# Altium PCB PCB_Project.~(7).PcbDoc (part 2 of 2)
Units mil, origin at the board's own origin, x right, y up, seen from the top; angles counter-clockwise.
Board outline 8500 x 3000 mil, 2 copper layers (Top Layer, Bottom Layer), stack 62 mil thick; 104 components, 48 nets, 317 pads, 0 vias.
Unrouted connection lines stored in the file: 193.

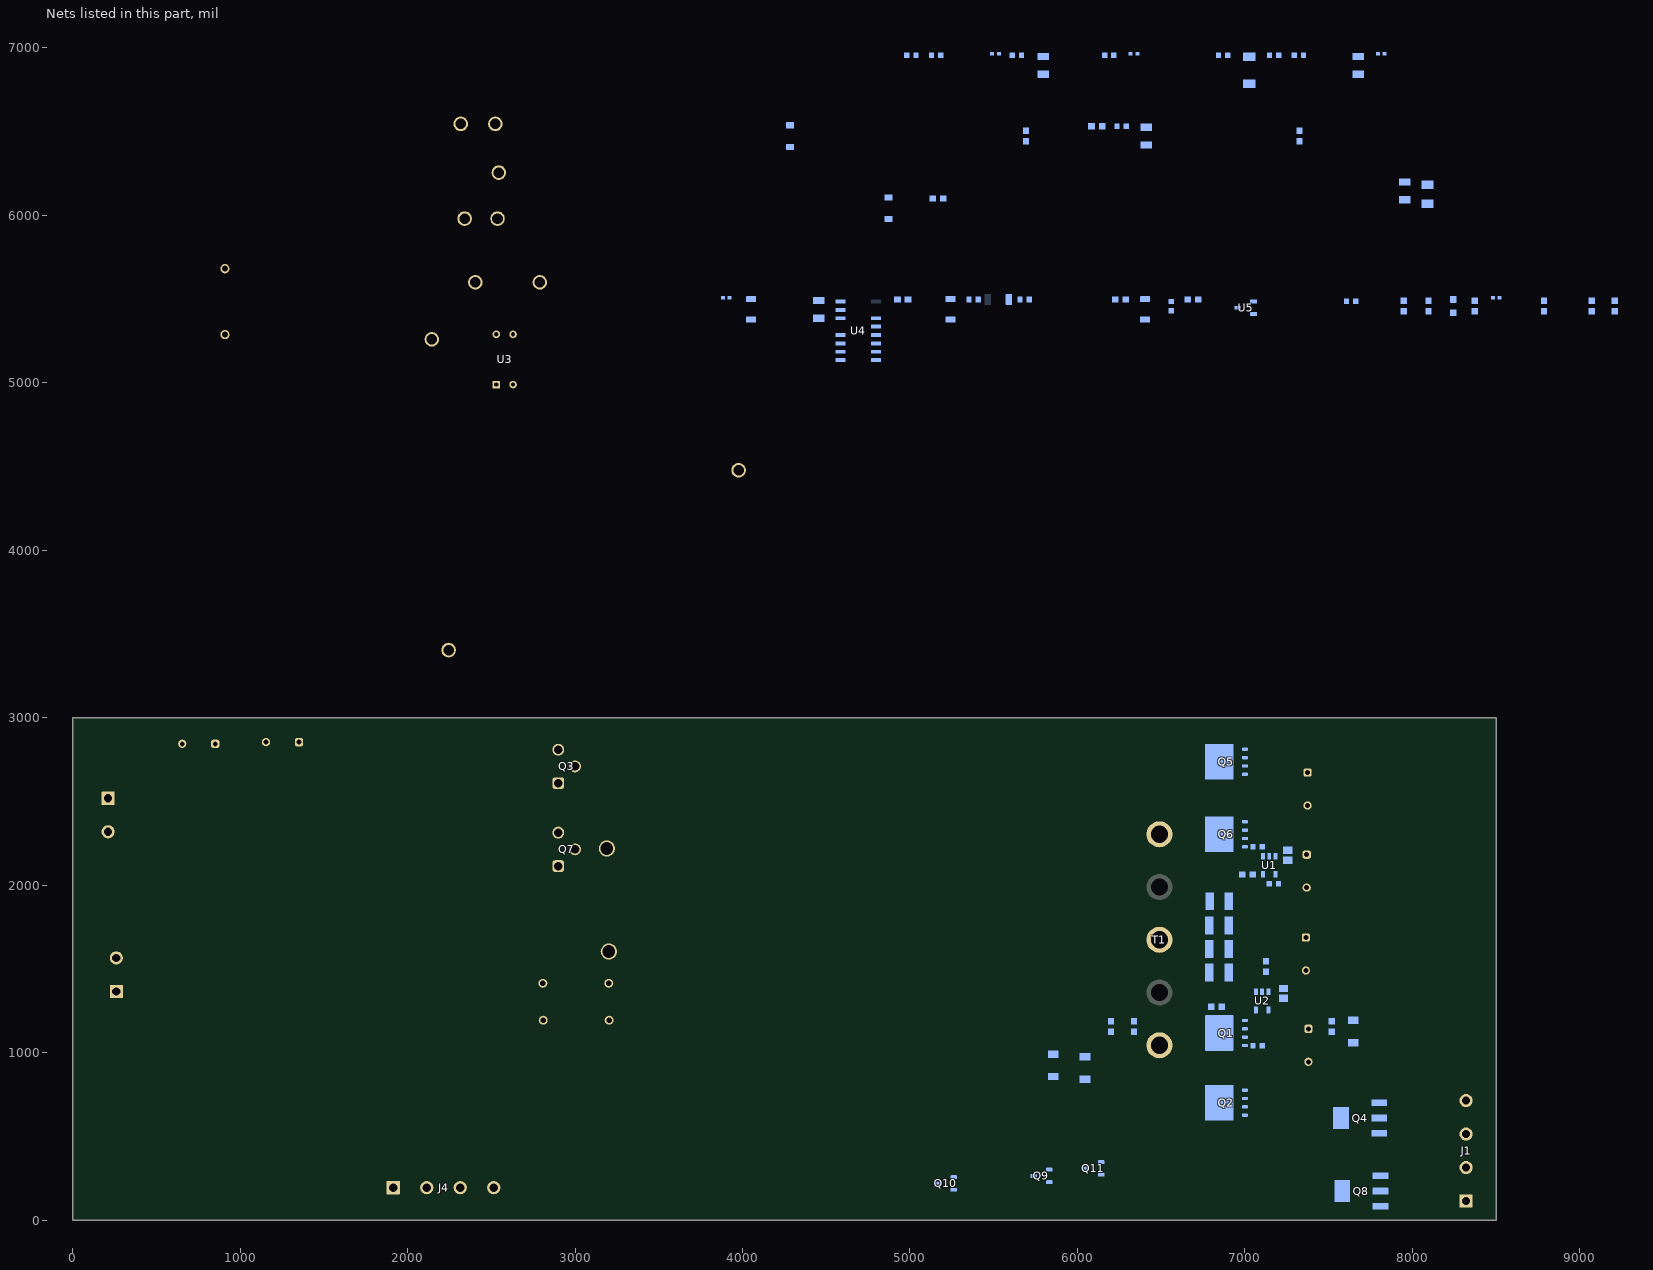
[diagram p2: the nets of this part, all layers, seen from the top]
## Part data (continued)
C15: library part CMP-0009595-2, "CAP, CERM, 1000 pF,  V, +/- 20%, E, D7xT6mm", Cap_Case=7x6x11mm, Manufacturer=TDK, Supplier Part Number 1=445-174535-ND, TempCo=E, Tolerance_%=20%, Value1=Unknown, Value2=V, ValueDisplayed=1000pF
C16: library part CMP-0008462-2, "CAP, CERM, 100 pF, 100 V, +/- 5%, C0G/NP0, 1206", Cap_Case=1206, Manufacturer=AVX, Supplier Part Number 1=478-1444-1-ND, TempCo=C0G/NP0, Tolerance_%=5%, Value1="0.701 ohm", Value2=100V, ValueDisplayed=100pF
C17 C21: library part CMP-0007380-4, "CAP, CERM, 1 uF, 16 V, +/- 10%, X7R, 0603", Cap_Case=0603, Manufacturer=MuRata, Supplier Part Number 1=490-10734-1-ND, TempCo=X7R, Tolerance_%=10%, Value1=Unknown, Value2=16V, ValueDisplayed=1uF
C18 C22: library part CMP-0007883-2, "CAP, CERM, 2.2 uF, 35 V, +/- 10%, X7R, 0805", Cap_Case=0805, Manufacturer=TDK, Supplier Part Number 1=445-14547-1-ND, TempCo=X7R, Tolerance_%=10%, Value1=Unknown, Value2=35V, ValueDisplayed=2.2uF
C19: library part CMP-0006941-4, "CAP, CERM, 4700 pF, 100 V, +/- 5%, C0G/NP0, 0603", Cap_Case=0603, Manufacturer=Kemet, Supplier Part Number 1=399-9974-1-ND, TempCo=C0G/NP0, Tolerance_%=5%, Value1=Unknown, Value2=100V, ValueDisplayed=4700pF
C20: library part CMP-0008693-2, "CAP, CERM, 4.7 uF, 25 V, +/- 10%, X7R, 1206", Cap_Case=1206, Manufacturer=TDK, Supplier Part Number 1=445-14797-1-ND, TempCo=X7R, Tolerance_%=10%, Value1=Unknown, Value2=25V, ValueDisplayed=4.7uF
C23 C25: library part CMP-0064913-2, "CAP, CERM, 150 pF, 50 V,+/- 5%, C0G/NP0, 0402", Cap_Case=0402, Manufacturer="Wurth Elektronik", Supplier Part Number 1=732-7476-1-ND, TempCo=C0G/NP0, Tolerance_%=5%, Value1=Unknown, Value2=50V, ValueDisplayed=150pF
C24: library part CMP-0008465-2, "CAP, CERM, 1000 pF, 100 V, +/- 5%, C0G/NP0, 1206", Cap_Case=1206, Manufacturer=AVX, Supplier Part Number 1=478-1450-1-ND, TempCo=C0G/NP0, Tolerance_%=5%, Value1="0.238 ohm", Value2=100V, ValueDisplayed=1000pF
C26: library part CMP-0064950-2, "CAP, CERM, 0.1 uF, 25 V,+/- 5%, C0G/NP0, 1206", Cap_Case=1206, Manufacturer=MuRata, Supplier Part Number 1=490-1767-1-ND, TempCo=C0G/NP0, Tolerance_%=5%, Value1=Unknown, Value2=25V, ValueDisplayed=0.1uF
C27: library part CMP-0006726-4, "CAP, CERM, 0.01 uF, 100 V, +/- 5%, X7R, 0603", Cap_Case=0603, Manufacturer=AVX, Supplier Part Number 1=478-3700-1-ND, TempCo=X7R, Tolerance_%=5%, Value1="0.098 ohm", Value2=100V, ValueDisplayed=0.01uF
C28 C29: library part CMP-0081062-1, "CAP, CERM, 10 µF, 25 V,+/- 5%, X7R, AEC-Q200 Grade 1, 1206", Cap_Case=1206_180, Manufacturer=Kemet, Supplier Part Number 1=399-15734-1-ND, TempCo=X7R, Tolerance_%=5%, Value2=25V, ValueDisplayed=10µF
C30: library part CMP-0006983-4, "CAP, CERM, 2200 pF, 50 V, +/- 10%, X7R, 0603", Cap_Case=0603, Manufacturer=Kemet, Supplier Part Number 1=399-5341-1-ND, TempCo=X7R, Tolerance_%=10%, Value1=Unknown, Value2=50V, ValueDisplayed=2200pF
C31 C34: library part CMP-0006982-4, "CAP, CERM, 220 pF, 50 V, +/- 10%, X7R, 0603", Cap_Case=0603, Manufacturer=Kemet, Supplier Part Number 1=399-5342-1-ND, TempCo=X7R, Tolerance_%=10%, Value1=Unknown, Value2=50V, ValueDisplayed=220pF
C32: library part CMP-0861060-1, "CAP, CERM, 1000 pF, 50 V,+/- 5%, X7R, 0402", Cap_Case=0402, Manufacturer=AVX, TempCo=X7R, Tolerance_%=5%, Value2=50V, ValueDisplayed=1000pF
C33: library part CMP-0007053-4, "CAP, CERM, 1000 pF, 100 V, +/- 10%, X7R, 0603", Cap_Case=0603, Manufacturer=TDK, Supplier Part Number 1=445-1298-1-ND, TempCo=X7R, Tolerance_%=10%, Value1=Unknown, Value2=100V, ValueDisplayed=1000pF
C35: library part CMP-0009024-2, "CAP, CERM, 22 uF, 25 V, +/- 20%, X5R, 1206_190", Cap_Case=1206, Manufacturer="Taiyo Yuden", Supplier Part Number 1=587-3246-1-ND, TempCo=X5R, Tolerance_%=20%, Value1=Unknown, Value2=25V, ValueDisplayed=22uF
Cr HS: library part CMP-0055026-1, "Pin Receptacle, .032-.046\" .075\" Dia, Gold, TH", Manufacturer=Mill-Max, Supplier Part Number 1=0312-015153427100-ND
D1 D2: library part CMP-0079240-2, "Diode, Schottky, 30 V, 1 A, AEC-Q101, SOD-123", Manufacturer=Nexperia, Value1=1A, Value2=0.56V
D3: library part CMP-0029162-2, "Diode, Ultrafast, 600 V, 1 A, AEC-Q101, SMAF", Manufacturer="Fairchild Semiconductor", Value1=1A, Value2=1.7V
ISNS1 TP7 TP8: library part CMP-0055149-2, "Test Point, Multipurpose, White, TH", Color=White, Manufacturer="Keystone Electronics", Supplier Part Number 1=36-5012-ND
J1 J4: library part CMP-0074939-1, "Terminal Block, 5.08 mm, 4x1, Brass, TH", Color=Blue, Current_A=15A, Manufacturer="On-Shore Technology", Supplier Part Number 1=ED2227-ND, Voltage_V=300V
J2 J3: library part CMP-0074910-1, "Terminal Block, 5.08 mm, 2x1, Brass, TH", Color=Blue, Current_A=15A, Manufacturer="On-Shore Technology", PartNumber=ED120/2DS, Supplier Part Number 1=ED1609-ND, Voltage_V=300V
Q1 Q2 Q5 Q6: library part CMP-0000958-3, "MOSFET, N-CH, 100 V, 17 A, DNK0008A (VSON-CLIP-8)", Alternate Manufacturer=None, Manufacturer="Texas Instruments", Supplier Part Number 1=296-37478-6-ND, Value2="48 nC"
Q3 Q7: library part CMP-0001171-3, "MOSFET, N-CH, 600 V, 22 A, TO-220AB", Alternate Manufacturer=None, Manufacturer="Infineon Technologies", Supplier Part Number 1=IPP60R099C7XKSA1-ND, Value2="42 nC"
Q4 Q8: library part CMP-0000361-2, "Transistor, PNP, 100 V, 1 A, AEC-Q101, SOT-223", Manufacturer="Diodes Inc.", Supplier Part Number 1=FZT593CT-ND, Value1="1 A", Value2=300
Q9: library part CMP-0001149-3, "MOSFET, N-CH, 600 V, 0.05 A, SOT-23", Alternate Manufacturer=None, Manufacturer="Diodes Inc.", Supplier Part Number 1=BSS127S-7DICT-ND, Value2="1.08 nC"
Q10 Q11: library part CMP-0000488-2, "Transistor, NPN, 60 V, 0.5 A, AEC-Q101, SOT-23", Manufacturer="ON Semiconductor", Supplier Part Number 1=MMBTA05LT1GOSCT-ND, Value1="0.5 A"
R1 R3: library part CMP-0022926-4, "RES, 22.1, 1%, 0.1 W, 0603", Manufacturer=Yageo, Power_W=100mW, Supplier Part Number 1=311-22.1HRCT-ND, TempCo="100 ppm/C", Tolerance_%=1%, Value2=0.1W, Value_Code=22R1, ValueDisplayed=22.1
R2 R4: library part CMP-0080488-1, "RES, 10.0 k, 1%, 0.1 W, 0603", Manufacturer="TT Electronics/IRC", Power_W=100mW, TempCo="100 ppm/C", Tolerance_%=1%, Value2=0.1W, Value_Code=10k0, ValueDisplayed=10.0k
R5: library part CMP-0017949-2, "RES, 187, 1%, 0.25 W, 1206", Manufacturer="Yageo America", Power_W=250mW, Supplier Part Number 1=311-187FRCT-ND, TempCo="100 ppm/C", Tolerance_%=1%, Value2=0.25W, Value_Code=187R, ValueDisplayed=187
R6 R9 R29: library part CMP-0023000-5, "RES, 2.00 k, 1%, 0.1 W, 0603", Manufacturer=Yageo, Power_W=100mW, Supplier Part Number 1=311-2.00KHRCT-ND, TempCo="100 ppm/C", Tolerance_%=1%, Value2=0.1W, Value_Code=2k00, ValueDisplayed=2.00k
R7 R12: library part CMP-0025885-5, "RES, 0, 5%, 0.1 W, 0603", Manufacturer=Yageo, Power_W=100mW, Supplier Part Number 1=311-0.0GRCT-ND, TempCo="200 ppm/C", Tolerance_%=5%, Value2=0.1W, Value_Code=0000, ValueDisplayed=0
R8: library part CMP-0022871-5, "RES, 1.21 k, 1%, 0.1 W, 0603", Manufacturer=Yageo, Power_W=100mW, Supplier Part Number 1=311-1.21KHRCT-ND, TempCo="100 ppm/C", Tolerance_%=1%, Value2=0.1W, Value_Code=1k21, ValueDisplayed=1.21k
R10: library part CMP-0027004-2, "RES, 0, 5%, 0.063 W, 0402", Manufacturer="Yageo America", Power_W=63mW, Supplier Part Number 1=311-0.0JRCT-ND, TempCo="200 ppm/C", Tolerance_%=5%, Value2=0.063W, Value_Code=0000, ValueDisplayed=0
R11: library part CMP-0023332-5, "RES, 9.09 k, 1%, 0.1 W, 0603", Manufacturer=Yageo, Power_W=100mW, Supplier Part Number 1=311-9.09KHRCT-ND, TempCo="100 ppm/C", Tolerance_%=1%, Value2=0.1W, Value_Code=9k09, ValueDisplayed=9.09k
R13: library part CMP-0022981-5, "RES, 2.05 k, 1%, 0.1 W, 0603", Manufacturer=Yageo, Power_W=100mW, Supplier Part Number 1=311-2.05KHRCT-ND, TempCo="100 ppm/C", Tolerance_%=1%, Value2=0.1W, Value_Code=2k05, ValueDisplayed=2.05k
R14: library part CMP-0022800-4, "RES, 147 k, 1%, 0.1 W, 0603", Manufacturer=Yageo, Power_W=100mW, Supplier Part Number 1=311-147KHRCT-ND, TempCo="100 ppm/C", Tolerance_%=1%, Value2=0.1W, Value_Code=147k
R15: library part CMP-0022711-2, "RES, 2.20, 1%, 0.1 W, 0603", Manufacturer=Panasonic, Power_W=100mW, Supplier Part Number 1=P2.2AJCT-ND, TempCo="200 ppm/C", Tolerance_%=1%, Value2=0.1W, Value_Code=2R20, ValueDisplayed=2.20
R16: library part CMP-0022684-3, "RES, 10.0 k, 1%, 0.1 W, 0603", Manufacturer=Panasonic, Power_W=100mW, Supplier Part Number 1=P10.0KHCT-ND, TempCo="100 ppm/C", Tolerance_%=1%, Value2=0.1W, Value_Code=10k0, ValueDisplayed=10.0k
R17 R19 R25: library part CMP-0087456-2, "3.3 MOhms ±1% 0.25W, 1/4W Chip Resistor 1206 (3216 Metric) Automotive AEC-Q200, High Voltage Thick Film", Manufacturer="Rohm Semiconductor", Power_W=250mW, TempCo=100ppm/°C, Tolerance_%=1%
R18: library part CMP-0026658-1, "RES, 10.0 k, 1%, 0.1 W, 0402", Manufacturer=Panasonic, Power_W=100mW, Supplier Part Number 1=P10.0KLCT-ND, TempCo="100 ppm/C", Tolerance_%=1%, Value2=0.1W, Value_Code=10k0, ValueDisplayed=10.0k
R20 R22: library part CMP-0023036-5, "RES, 33.2 k, 1%, 0.1 W, 0603", Manufacturer=Yageo, Power_W=100mW, Supplier Part Number 1=311-33.2KHRCT-ND, TempCo="100 ppm/C", Tolerance_%=1%, Value2=0.1W, Value_Code=33k2, ValueDisplayed=33.2k
R21: library part CMP-0022109-5, "RES, 1.00 k, 1%, 0.1 W, AEC-Q200 Grade 0, 0603", Manufacturer=Vishay-Dale, Power_W=100mW, Supplier Part Number 1=541-1.00KHCT-ND, TempCo="100 ppm/C", Tolerance_%=1%, Value2=0.1W, Value_Code=1k00, ValueDisplayed=1.00k
R23 R26: library part CMP-0022735-5, "RES, 100 k, 1%, 0.1 W, 0603", Manufacturer=Yageo, Power_W=100mW, Supplier Part Number 1=311-100KHRCT-ND, TempCo="100 ppm/C", Tolerance_%=1%, Value2=0.1W, Value_Code=100k
R24: library part CMP-0023092-4, "RES, 3.01 M, 1%, 0.1 W, 0603", Manufacturer=Yageo, Power_W=100mW, Supplier Part Number 1=311-3.01MHRCT-ND, TempCo="100 ppm/C", Tolerance_%=1%, Value2=0.1W, Value_Code=3M01, ValueDisplayed=3.01M
R27: library part CMP-0093609-1, "0Ω ±0 0.25W 1206 Thick Film Chip Resistor AEC-Q200 compliant", Manufacturer="Stackpole Electronics", Operating Temperature Range="-55°C to +155°C", Power_W=250mW
R28: library part CMP-0022763-5, "RES, 11.0 k, 1%, 0.1 W, 0603", Manufacturer=Yageo, Power_W=100mW, Supplier Part Number 1=311-11.0KHRCT-ND, TempCo="100 ppm/C", Tolerance_%=1%, Value2=0.1W, Value_Code=11k0, ValueDisplayed=11.0k
R30: library part CMP-0096703-1, "NTC Thermistor 470k 0603 (1608 Metric)", B Tolerance=3%, Digikey Part Number=495-B57371V2474J060CT-ND, Manufacturer=TDK, Mouser Part Number=871-B57371V2474J060, Operating Temperature Range="-55°C to +125°C", Power_W=180mW, Tolerance_%=5%
R31: library part CMP-0022828-5, "RES, 16.2 k, 1%, 0.1 W, 0603", Manufacturer=Yageo, Power_W=100mW, Supplier Part Number 1=311-16.2KHRCT-ND, TempCo="100 ppm/C", Tolerance_%=1%, Value2=0.1W, Value_Code=16k2, ValueDisplayed=16.2k
R32: library part CMP-0022941-4, "RES, 249 k, 1%, 0.1 W, 0603", Manufacturer=Yageo, Power_W=100mW, Supplier Part Number 1=311-249KHRCT-ND, TempCo="100 ppm/C", Tolerance_%=1%, Value2=0.1W, Value_Code=249k
R33: library part CMP-0023050-5, "RES, 35.7 k, 1%, 0.1 W, 0603", Manufacturer=Yageo, Power_W=100mW, Supplier Part Number 1=311-35.7KHRCT-ND, TempCo="100 ppm/C", Tolerance_%=1%, Value2=0.1W, Value_Code=35k7, ValueDisplayed=35.7k
T1: library part CMP-0120310-1, "Backlight LLC Transformer", Frequency_Fixed=80-250kHz, Manufacturer="Payton Planar", Operating Temperature Range=to, Voltage_Isolation_Vrms=2500VDC
TP1 TP2 TP3 TP4: library part CMP-0055148-2, "Test Point, Multipurpose, Black, TH", Color=Black, Manufacturer="Keystone Electronics", Supplier Part Number 1=36-5011-ND
TP5 Vin1: library part CMP-0055147-2, "Test Point, Multipurpose, Red, TH", Color=Red, Manufacturer="Keystone Electronics", Supplier Part Number 1=36-5010-ND
TP6: library part CMP-0055150-2, "Test Point, Multipurpose, Orange, TH", Color=Orange, Manufacturer="Keystone Electronics", Supplier Part Number 1=36-5013-ND
U1 U2: library part CMP-0013047-3, "High-Frequency Multi-Mode Synchronous Rectifier Controller, DBV0005A (SOT-23-5)", Alternate Manufacturer="Texas Instruments", Alternate PartNumber=UCC24612-2DBVR
U3: library part CMP-0083653-1, "Optocoupler, 5.3 kV, 100-200% CTR, SMT", Manufacturer=Vishay-Semiconductor, Supplier Part Number 1=VO618A-3-ND, Voltage_Isolation_Vrms=5.3kV
U4: library part CMP-0095299-1, "750kHz Wide VIN/VOUT Range LLC Controller Optimized for Light Load Efficiency", Manufacturer="Texas Instruments", Max Supply Voltage=18.5V, Operating Temperature Range="-40°C to +150°C", Switching Frequency=30-750kHz
U5: library part CMP-0033066-1, "Low-Voltage Adjustable Precision Shunt Regulator, 129 ppm / degC, 80 mA, 0 to 70 degC, 3-pin SOT-23 (DBZ), Green (RoHS & no Sb/Br)", Manufacturer="Texas Instruments", Rating=Catalog, Temp Coeff(Max)(ppm/ degree C)=129

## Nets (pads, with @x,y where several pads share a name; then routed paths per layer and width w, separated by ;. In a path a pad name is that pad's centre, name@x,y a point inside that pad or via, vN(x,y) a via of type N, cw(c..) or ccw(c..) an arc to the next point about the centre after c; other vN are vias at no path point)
5VP_BL: C20.1 R24.2 R26.2 U4.8
BLK_BL: C32.1 Q9.2 R27.1 R33.2 U4.3
EVDD: C2.2 C3.2 C4.2 C5.2 C8.2 C9.2 C10.1 C11.1 C12.1 C17.1 C21.1 J1.1 J1.2 R10.2 T1.9 TP5.1 U1.4 U2.4
FB_BL: C24.1 U3.4 U4.5
HO_BL: D1.2 Q4.1 U4.15
HS_BL: C26.2 HS.1 Q3.3 Q4.2 Q4.4 Q7.2 R2.1 U4.16
HVBUS: C1.1 C6.2 C7.2 J2.1 J2.2 Q3.2 R17.2 Vin1.1
ISNS_BL: C13.2 C16.1 ISNS1.1 R5.2 U4.9
LLC_VCC_BL: C35.1 J4.3 J4.4 R15.1 R29.2 U4.12
LO_BL: D2.2 Q8.1 U4.11
NetC1_2: C1.2 C13.1 C14.1 Cr.1
NetC18_1: C18.1 U1.3
NetC19_1: C19.1 C23.1 R10.1 R11.2 R14.2 TP6.1
NetC19_2: C19.2 R8.2
NetC22_1: C22.1 U2.3
NetC23_2: C23.2 R16.2
NetC25_1: C25.1 R14.1 R16.1 R20.1 R22.2 R28.2 U5.1
NetC25_2: C25.2 C27.2 R13.1 U3.2 U5.2
NetC26_1: C26.1 D3.1 U4.14
NetC27_1: C27.1 R20.2
NetC28_1: C28.1 C29.1 R21.1 R23.2
NetC30_1: C30.1 R30.2 U4.4
NetC31_1: C31.1 R24.1 R32.2 U4.6
NetC33_1: C33.1 Q9.1 R29.1
NetC34_1: C34.1 R26.1 R31.2 U4.7
NetD1_1: D1.1 R1.1
NetD2_1: D2.1 R3.1
NetD3_2: D3.2 R15.2
NetQ3_1: Q3.1 Q4.3 R1.2 R2.2
NetQ7_1: Q7.1 Q8.3 R3.2 R4.2
NetQ9_3: Q9.3 R25.1
NetQ10_1: Q10.1 Q11.1 Q11.3 R23.1
NetQ10_3: Q10.3 R22.1
NetR6_1: R6.1 U1.5
NetR7_2: R7.2 U1.1
NetR8_1: R8.1 R11.1 R13.2 U3.1
NetR9_1: R9.1 U2.5
NetR12_2: R12.2 U2.1
NetR17_1: R17.1 R19.2
NetR18_2: R18.2 TP7.1 U3.3
NetR19_1: R19.1 R25.2
NetR21_2: R21.2 TP8.1
PGND: C6.1 C7.1 C14.2 C15.2 C16.2 C20.2 C24.2 C30.2 C31.2 C32.2 C33.2 C34.2 C35.2 J3.1 J3.2 J4.1 J4.2 Q7.3 Q8.2 Q8.4 R4.1 R5.1 R18.1 R30.1 R31.1 R32.1 R33.1 TP3.1 TP4.1 U4.10
SGND: C2.1 C3.1 C4.1 C5.1 C8.1 C9.1 C10.2 C11.2 C12.2 C15.1 C17.2 C18.2 C21.2 C22.2 C28.2 C29.2 J1.3 J1.4 Q1.1 Q1.2 Q1.3 Q2.1 Q2.2 Q2.3 Q5.1 Q5.2 Q5.3 Q6.1 Q6.2 Q6.3 Q10.2 Q11.2 R28.1 TP1.1 TP2.1 U1.2 U2.2 U5.3
VD1: Q5.5 Q5.6 Q5.7 Q5.8 Q5.9@6846.42,2737.64 Q6.5 Q6.6 Q6.7 Q6.8 Q6.9@6846.46,2305 R6.2 T1.11
VD2: Q1.5 Q1.6 Q1.7 Q1.8 Q1.9@6846.37,1118.42 Q2.5 Q2.6 Q2.7 Q2.8 Q2.9@6846.42,702.64 R9.2 T1.7
VG1: Q5.4 Q6.4 R7.1
VG2: Q1.4 Q2.4 R12.1
pads on no net: Q1.9@6819.4,1066.06 Q1.9@6819.4,1118.42 Q1.9@6819.4,1170.78 Q1.9@6859.36,1118.42 Q1.9@6864.68,1066.06 Q1.9@6864.68,1118.42 Q1.9@6864.68,1170.78 Q1.9@6909.95,1066.06 Q1.9@6909.95,1118.42 Q1.9@6909.95,1170.78 Q1.9@6921.57,1025.02 Q1.9@6921.57,1211.83 Q2.9@6819.45,650.28 Q2.9@6819.45,702.64 Q2.9@6819.45,755 Q2.9@6859.41,702.64 Q2.9@6864.72,650.28 Q2.9@6864.72,702.64 Q2.9@6864.72,755 Q2.9@6910,650.28 Q2.9@6910,702.64 Q2.9@6910,755 Q2.9@6921.61,609.23 Q2.9@6921.61,796.04 Q5.9@6819.45,2685.28 Q5.9@6819.45,2737.64 Q5.9@6819.45,2790 Q5.9@6859.41,2737.64 Q5.9@6864.72,2685.28 Q5.9@6864.72,2737.64 Q5.9@6864.72,2790 Q5.9@6910,2685.28 Q5.9@6910,2737.64 Q5.9@6910,2790 Q5.9@6921.61,2644.23 Q5.9@6921.61,2831.04 Q6.9@6819.49,2252.64 Q6.9@6819.49,2305 Q6.9@6819.49,2357.36 Q6.9@6859.45,2305 Q6.9@6864.76,2252.64 Q6.9@6864.76,2305 Q6.9@6864.76,2357.36 Q6.9@6910.04,2252.64 Q6.9@6910.04,2305 Q6.9@6910.04,2357.36 Q6.9@6921.65,2211.59 Q6.9@6921.65,2398.41 R27.2 T1.8 T1.10 U4.1

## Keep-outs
Keep-Out Layer:
  text ".Layer_Name" at 577,-858.49 h60

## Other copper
Top Layer:
  text ".Layer_Name" at 577,-858.49 h60
Bottom Layer:
  text ".Layer_Name" at 577,-858.49 h60

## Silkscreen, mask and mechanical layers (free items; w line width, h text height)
Top Overlay:
  text "'.PRJ_Number'.PCB_Rev" at 3505,160 h108.27
  text ".Layer_Name" at 577,-858.49 h60
Bottom Overlay:
  text ".Layer_Name" at 577,-858.49 h60
Top Paste:
  text ".Layer_Name" at 577,-858.49 h60
Bottom Paste:
  text ".Layer_Name" at 577,-858.49 h60
Top Solder:
  text ".Layer_Name" at 577,-858.49 h60
  text ".Layer_Name" at 577,-858.49 h60
Bottom Solder:
  text ".Layer_Name" at 577,-858.49 h60
Drill Guide:
  text ".Layer_Name" at 577,-858.49 h60
M1 Board Outline:
  the board outline again, w10
  text ".Layer_Name" at 577,-858.49 h60
M2 Board Dimensions:
  rectangle: 0,-275 125,-150
  rectangle: 125,-400 500,-275
  lines w7: 0,-275 1000,-275 ; 125,-400 125,-150 ; 250,-400 250,-150 ; 500,-400 500,-150 ; 750,-400 750,-150 ; 0,-400 1000,-400 1000,-150 0,-150 0,-400
  text ".Layer_Name" at 577,-858.49 h60
M3 3D STEP Top:
  text ".Layer_Name" at 577,-858.49 h60
M4 3D STEP Bottom:
  text ".Layer_Name" at 577,-858.49 h60
M5 Assembly Top:
  lines w10: -292,-930.17 6308,-930.17 ; -292,-726.83 6310,-726.83 ; -292,-523.5 -292,-1133.5 3713,-1133.5 6310,-1133.5 6310,-523.5 -291.5,-523.5 -291.5,-1133.5 1284,-1133.5 ; 2173,-1133.5 2173,-523.5 ; 3440,-726.83 3440,-523.5 ; 4280,-726.83 4280,-523.5 ; 4902,-1140 4902,-937.17
  text "COMPONENTS MARKED 'DNP' SHOULD NOT BE POPULATED." at 1153.5,-318.5 h60
  text "ASSEMBLY VARIANT:" at 1153,-434 h60
  text ".VariantName" at 2189,-434 h60
  text "PCB VIEWED FROM TOP SIDE" at -228.5,-655.67 h60
  text "BOARD #:" at 2248,-655.67 h60
  text ".PRJ_Number" at 2793.5,-655.67 h60
  text "REV:" at 3638,-655.67 h60
  text ".PCB_Rev" at 3929.5,-655.67 h60
  text "SVN REV:" at 4476,-655.67 h60
  text ".VersionControl_RevNumber" at 4982,-655.67 h60
  text "TID #:" at 2248,-859 h60
  text ".TID" at 2793.5,-859 h60
  text "PLOT NAME =" at -228.5,-1064.34 h60
  text ".plot_File_Name" at 577,-1064.34 h60
  text "GENERATED    :" at 2250,-1064.34 h60
  text ".Print_Date" at 3119.5,-1064.34 h60
  text ".Print_Time" at 3848.5,-1064.34 h60
  text "TEXAS INSTRUMENTS" at 5113,-1064.34 h60
M6 Assembly Bottom:
  lines w10: -292.5,-727.33 6309.5,-727.33 ; -290.5,-930.67 6309.5,-930.67 ; 1115.5,-1140.5 1115.5,-937.67 ; 1737.5,-727.33 1737.5,-524 ; 2577.5,-727.33 2577.5,-524 ; 3844.5,-1134 3844.5,-524 ; 4733.5,-1134 6309,-1134 6309,-524 -292.5,-524 -292.5,-1134 2304.5,-1134 6309.5,-1134 6309.5,-524
  text "COMPONENTS MARKED 'DNP' SHOULD NOT BE POPULATED." at 6102,-318 h60
  text ".VariantName" at 5058,-434 h60
  text "ASSEMBLY VARIANT:" at 6097,-434 h60
  text ".VersionControl_RevNumber" at 1035.5,-656.17 h60
  text "SVN REV:" at 1541.5,-656.17 h60
  text ".PCB_Rev" at 2088,-656.17 h60
  text "REV:" at 2379.5,-656.17 h60
  text ".PRJ_Number" at 3224,-656.17 h60
  text "BOARD #:" at 3769.5,-656.17 h60
  text "PCB VIEWED FROM BOTTOM SIDE" at 6246,-656.17 h60
  text ".TID" at 3224,-859.5 h60
  text "TID #:" at 3769.5,-859.5 h60
  text "TEXAS INSTRUMENTS" at 904.5,-1064.84 h60
  text ".Print_Time" at 2169,-1064.84 h60
  text ".Print_Date" at 2898,-1064.84 h60
  text "GENERATED    :" at 3767.5,-1064.84 h60
  text ".plot_File_Name" at 5440.5,-1064.84 h60
  text "PLOT NAME =" at 6246,-1064.84 h60
M9 Title Sheet:
  drawing of 57 lines, arcs and shapes, not listed
  text "1" at 739.84,8036.5 h70
  text "2" at 3235.5,8036.5 h70
  text "3" at 5724.84,8036.5 h70
  text "4" at 8231.51,8036.5 h70
  text "5" at 10730.5,8036.5 h70
  text "6" at 13235.5,8036.5 h70
  text "A" at -416.5,6893.5 h70
  text "A" at 14383.5,6893.5 h70
  text "B" at -416.5,4513.5 h70
  text "B" at 14383.5,4513.5 h70
  text "C" at -416.5,2138.5 h70
  text "C" at 14383.5,2138.5 h70
  text "PROJECT TITLE:" at 11343.5,277.5 h45
  text ".PRJ_Title" at 11393.5,144.17 h70
  text "DESIGNED FOR:" at 11343.5,-23.5 h45
  text ".PRJ_Customer" at 11393.5,-163.5 h70
  text "D" at -416.5,-231.5 h70
  text "D" at 14383.5,-231.5 h70
  text "FILE NAME:" at 11343.5,-323.5 h45
  text ".PCB_File_Name_No_Path" at 11393.5,-443.5 h70
  text "Texas Instruments (TI) and/or its licensors do not warrant the accuracy or completeness of this specification" at 6374,-605.34 h45
  text "ENGINEER:" at 11343.5,-613.5 h45
  text "LAYOUT BY:" at 12848.5,-613.5 h45
  text "or any information contained therein. TI and/or its licensors do not warrant that this design will meet" at 6329.01,-718 h45
  text ".PRJ_Engineer" at 11393.5,-768.49 h70
  text ".PCB_Layout" at 12899,-768.49 h70
  text "the specifications, will be suitable for your application or fit for any particular purpose, or will operate in" at 6329.01,-830.67 h45
  text ".Layer_Name" at 577,-858.49 h60
  text "ALTIUM DESIGNER VERSION:" at 12848.5,-923.5 h45
  text "an implementation. TI and/or its licensors do not warrant that the design is production worthy. You should" at 6329.01,-943.33 h45
  text "completely validate and test your design implementation to confirm the system functionality for your application." at 6374,-1056 h45
  text ".print_Scale" at 11393.5,-1056.83 h70
  text ".Application_BuildNumber" at 12899,-1056.83 h70
  text "1" at 739.84,-1263.5 h70
  text "2" at 3235.5,-1263.5 h70
  text "3" at 5724.84,-1263.5 h70
  text "4" at 8231.51,-1263.5 h70
  text "5" at 10730.5,-1263.5 h70
  text "6" at 13235.5,-1263.5 h70
M10 Fab Notes:
  drawing of 189 lines, arcs and shapes, not listed
  text "DESIGN INFORMATION" at 12382.02,6356.17 h60
  text "MIN. TRACK WIDTH:" at 11737.46,6224.05 h60
  text "8" at 12833.7,6224.05 h60
  text "MIL" at 12988.46,6224.05 h60
  text "7.874" at 12667.32,6102.36 h60
  text "MIN. CLEARANCE:" at 11737.46,6099.92 h60
  text "MIL" at 12988.46,6099.92 h60
  text "MIN. VIA PAD SIZE:" at 11737.46,5975.8 h60
  text "24" at 12803.71,5975.8 h60
  text "MIL" at 12988.46,5975.8 h60
  text "0.05mm (2MIL)" at 12432.46,5845.9 h60
  text "MINIMUM ANNULAR RING" at 11408.23,5837.67 h60
  text "EXTERNAL" at 13140.46,5837.67 h60
  text "PER" at 11608.23,5727.55 h60
  text "IPC-D-275 CLASS 2 LEVEL C" at 11828.23,5727.54 h60
  text "MIL, HOLES" at 13316.46,5627.07 h60
  text "+/-" at 12924,5618.48 h60
  text "+/-" at 13778,5618.48 h60
  text "REGISTRATION TOLERANCES:" at 11408.23,5617.42 h60
  text "METAL" at 12608,5617.42 h60
  text "5" at 13184.2,5617.42 h60
  text "3" at 14017.2,5617.42 h60
  text "MIL" at 14133.46,5617.42 h60
  text "HOLE SIZE TOLERANCE (UNLESS OTHERWISE SPECIFIED):" at 11408.23,5519.1 h60
  text "+/-" at 13778,5516.23 h60
  text "3" at 14017.2,5515.17 h60
  text "MIL" at 14133.46,5515.17 h60
  text "MATERIAL:" at 11333.46,5377.52 h60
  text "FR-4 High Tg" at 12319.9,5249 h60
  text "X" at 12175.46,5241.01 h60
  text "FR-4" at 11754.46,5236.49 h60
  text "OTHER" at 13242.46,5236.49 h60
  text "62 MIL (1.6mm) +/-10%" at 12074.56,5093.46 h60
  text "X" at 11954.46,5091.01 h60
  text "THICKNESS:" at 11408.23,5085.24 h60
  text "OTHER" at 13359.46,5085.24 h60
  text "TOLERANCE:" at 11408.23,4946.92 h60
  text "X" at 12256.46,4946.92 h60
  text "ANSI IPC-6012 TYPE 3 CLASS 2" at 12434.48,4946.92 h60
  text "OTHER +/-" at 12434.46,4802.73 h60
  text "BOW & TWIST:" at 11408.23,4657.54 h60
  text "X" at 12256.46,4657.54 h60
  text "ANSI IPC-6012 TYPE 3 CLASS 2" at 12434.48,4657.54 h60
  text "OTHER +/-" at 12434.46,4510.85 h60
  text "DRILLING:" at 11333.46,4380.23 h60
  text "NC_DRILL FILES" at 13094.46,4275.04 h60
  text "REFERENCE:" at 11408.23,4271.1 h60
  text "X" at 12065.46,4271.01 h60
  text "AS SHOWN" at 12243.46,4271.1 h60
  text "X" at 12966.46,4271.1 h60
  text "OTHER" at 13392.46,4128.85 h60
  text "PTH COPPER THICKNESS:" at 11407.91,4125.32 h60
  text "X" at 12547.14,4125.32 h60
  text "20-30 um" at 12675.14,4125.32 h60
  text "BOARD FINISH:" at 11333.46,3977.73 h60
  text "SILKSCREEN:" at 11488.68,3867.6 h60
  text "X" at 12446.46,3867.6 h60
  text "TOP" at 12563.46,3867.6 h60
  text "X" at 12956.46,3867.6 h60
  text "BOTTOM" at 13074.46,3867.6 h60
  text "SILKSCREEN COLOR:" at 11488.68,3712.41 h60
  text "X" at 12445.46,3712.41 h60
  text "WHITE" at 12563.46,3712.41 h60
  text "OTHER" at 13074.46,3712.41 h60
  text "X" at 12576.46,3568.96 h60
  text "GREEN" at 12694.46,3568.96 h60
  text "OTHER" at 13312.46,3568.96 h60
  text "SOLDER RESIST COLOR:" at 11488.68,3562.1 h60
  text "X" at 12576.46,3414.71 h60
  text "MATTE" at 12694.46,3414.71 h60
  text "SEMI-GLOSS" at 13312,3414.07 h60
  text "IMMERSION GOLD (ENIG)" at 12394.46,3241.94 h60
  text "ENEPIG" at 13732,3234.72 h60
  text "SURFACE FINISH:" at 11333.46,3233.72 h60
  text "X" at 12216.46,3233.72 h60
  text "IMM. TIN/SILVER OR EQUIV" at 11663,3096.4 h60
  text "OTHER" at 13094.46,3092.47 h60
  text "ARRAY/PANEL:" at 11333.46,2937.09 h60
  text "CUT AND TRIM PER M1 BOARD OUTLINE" at 12394.46,2928.87 h60
  text "N.C. ROUTE" at 12394.46,2792.9 h60
  text "X" at 13082.46,2792.9 h60
  text "V. SCORE" at 13260.46,2792.9 h60
  text "CERTIFICATION:" at 11333.46,2663.77 h60
  text "MATERIALS AND WORKMANSHIP FOR ALL PCBS" at 12058.46,2663.77 h60
  text "TO MEET OR EXCEED THE REQUIREMENTS OF:" at 12058.46,2569.71 h60
  text "X" at 11695.97,2441.08 h60
  text "ANSI IPC-A-600F CLASS ->" at 11823.96,2441.08 h60
  text "X" at 13471.97,2441.08 h60
  text "2" at 13581.96,2441.08 h60
  text "1" at 13266.96,2439.58 h60
  text "3" at 13935.96,2439.58 h60
  text "X" at 12507.97,2293.39 h60
  text "RoHS" at 12635.96,2293.39 h60
  text "OTHER" at 13280.36,2293.39 h60
  text "PER ORDER" at 13677.42,2293.39 h60
  text "ALL BOARDS MUST MEET OR EXCEED UL94-V0 REQUIREMENTS." at 11361,2139.57 h60
  text "PCB MUST BEAR THE UL94V-0 UL REGISTERED MATERIAL ID NUMBER" at 11361,2023.5 h60
  text "ADDITIONAL REQUIREMENTS:" at 11333.46,1854.08 h60
  text "MICROSECTION:" at 11408.23,1746.95 h60
  text "YES" at 12313.96,1746.95 h60
  text "REQUIRED" at 13175.46,1602.62 h60
  text "BARE BOARD ELEC. TEST:" at 11408.23,1599.76 h60
  text "NONE" at 12713.96,1599.76 h60
  text "X" at 13057.46,1599.76 h60
  text "PER ORDER" at 13767.46,1599.76 h60
  text "XX MIL VIAS REQUIRE NON-CONDUCTIVE FILL AND PLANARIZE" at 11576.38,1394.82 h59
  text "XX MIL VIAS REQUIRE CONDUCTIVE FILL AND PLANARIZE" at 11584.38,1290.84 h60
  text "OUTER XX MIL TRACES REQUIRE 50 OHM SINGLE-ENDED IMPEDANCE" at 11583.39,1127.46 h58
  text "LAYER 2 & 3 (INNER LAYERS) XX MIL WIDE, XX MIL SPACE / TRACES REQUIRE 100 OHM DIFFERENTIAL IMPEDANCE" at 11575.39,891.74 h60
  text ".Layer_Name" at 577,-858.49 h60
M11 Gerber Information:
  lines w10: -292,-930.17 6308,-930.17 ; -292,-726.83 6310,-726.83 ; -292,-523.5 -292,-1133.5 3713,-1133.5 6310,-1133.5 6310,-523.5 -291.5,-523.5 -291.5,-1133.5 1284,-1133.5 ; 2173,-1133.5 2173,-523.5 ; 3440,-726.83 3440,-523.5 ; 4280,-726.83 4280,-523.5 ; 4902,-1140 4902,-937.17
  text "ALL ARTWORK VIEWED FROM TOP SIDE" at -228.5,-655.67 h60
  text "BOARD #:" at 2248,-655.67 h60
  text ".PRJ_Number" at 2793.5,-655.67 h60
  text "REV:" at 3638,-655.67 h60
  text ".PCB_Rev" at 3929.5,-655.67 h60
  text "SVN REV:" at 4476,-655.67 h60
  text ".VersionControl_RevNumber" at 4982,-655.67 h60
  text "LAYER NAME =" at -228.5,-858.49 h60
  text "TID #:" at 2248,-859 h60
  text ".TID" at 2793.5,-859 h60
  text "PLOT NAME =" at -228.5,-1064.34 h60
  text ".plot_File_Name" at 577,-1064.34 h60
  text "GENERATED    :" at 2250,-1064.34 h60
  text ".Print_Date" at 3119.5,-1064.34 h60
  text ".Print_Time" at 3848.5,-1064.34 h60
  text "TEXAS INSTRUMENTS" at 5113,-1064.34 h60
M12 Stackup:
  drawing of 191 lines, arcs and shapes, not listed
  text "Layer" at 9821.59,7874.94 h60
  text "Name" at 10231.51,7874.94 h60
  text "Material" at 11161.25,7874.94 h60
  text "Thickness" at 12021.02,7874.94 h60
  text "Constant" at 12670.85,7874.94 h60
  text "Board Layer Stack" at 13240.71,7874.94 h60
  text "Top Overlay" at 10231.51,7754.94 h60
  text "Top Solder" at 10231.51,7634.94 h60
  text "Solder Resist" at 11161.25,7634.94 h60
  text "0.40mil" at 12021.02,7634.94 h60
  text "3.5" at 12670.85,7634.94 h60
  text "1" at 9821.59,7514.94 h60
  text "Top Layer" at 10231.51,7514.94 h60
  text "1.40mil" at 12021.02,7514.94 h60
  text "Dielectric1" at 10231.51,7394.94 h60
  text "FR-4 High Tg" at 11161.25,7394.94 h60
  text "59.20mil" at 12021.02,7394.94 h60
  text "4.8" at 12670.85,7394.94 h60
  text "2" at 9821.59,7274.94 h60
  text "Bottom Layer" at 10231.51,7274.94 h60
  text "1.40mil" at 12021.02,7274.94 h60
  text "Bottom Solder" at 10231.51,7154.94 h60
  text "Solder Resist" at 11161.25,7154.94 h60
  text "0.40mil" at 12021.02,7154.94 h60
  text "3.5" at 12670.85,7154.94 h60
  text "Bottom Overlay" at 10231.51,7034.94 h60
  text ".Layer_Name" at 577,-858.49 h60
M13 Component Bodies Top:
  text ".Layer_Name" at 577,-858.49 h60
M14 Component Bodies Bottom:
  text ".Layer_Name" at 577,-858.49 h60
M15 Courtyards Top:
  text ".Layer_Name" at 577,-858.49 h60
M16 Courtyards Bottom:
  text ".Layer_Name" at 577,-858.49 h60
Drill Drawing:
  text ".Layer_Name" at 577,-858.49 h60
M17 Embedded Cavity:
  text ".Layer_Name" at 577,-858.49 h60
M18 Embedded Assembly:
  text ".Layer_Name" at 577,-858.49 h60
M19 Embedded Keepout:
  text ".Layer_Name" at 577,-858.49 h60

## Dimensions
0,-400 to 1000,-400 on M2 Board Dimensions
0,0 to 8500,0 on M2 Board Dimensions
0,0 to 0,3000 on M2 Board Dimensions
